VERSION 5.4 ;
NAMESCASESENSITIVE ON ;
BUSBITCHARS "[]" ;
DIVIDERCHAR "/" ;
UNITS
  DATABASE MICRONS 2000 ;
END UNITS
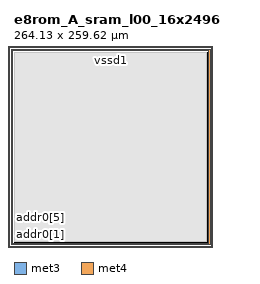
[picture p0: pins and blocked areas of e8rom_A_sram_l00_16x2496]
MACRO e8rom_A_sram_l00_16x2496
   CLASS BLOCK ;
   SIZE 264.13 BY 259.62 ;
   SYMMETRY X Y R90 ;
   PIN clk0
      DIRECTION INPUT ;
      PORT
         LAYER met3 ;
         RECT  -7.48 8.99 -7.1 9.37 ;
      END
   END clk0
   PIN cs0
      DIRECTION INPUT ;
      PORT
         LAYER met4 ;
         RECT  25.365 -7.48 25.745 -7.1 ;
      END
   END cs0
   PIN addr0[0]
      DIRECTION INPUT ;
      PORT
         LAYER met4 ;
         RECT  32.23 -7.48 32.61 -7.1 ;
      END
   END addr0[0]
   PIN addr0[1]
      DIRECTION INPUT ;
      PORT
         LAYER met4 ;
         RECT  34.27 -7.48 34.65 -7.1 ;
      END
   END addr0[1]
   PIN addr0[2]
      DIRECTION INPUT ;
      PORT
         LAYER met4 ;
         RECT  36.31 -7.48 36.69 -7.1 ;
      END
   END addr0[2]
   PIN addr0[3]
      DIRECTION INPUT ;
      PORT
         LAYER met4 ;
         RECT  38.35 -7.48 38.73 -7.1 ;
      END
   END addr0[3]
   PIN addr0[4]
      DIRECTION INPUT ;
      PORT
         LAYER met3 ;
         RECT  -7.48 33.89 -7.1 34.27 ;
      END
   END addr0[4]
   PIN addr0[5]
      DIRECTION INPUT ;
      PORT
         LAYER met3 ;
         RECT  -7.48 33.145 -7.1 33.525 ;
      END
   END addr0[5]
   PIN addr0[6]
      DIRECTION INPUT ;
      PORT
         LAYER met3 ;
         RECT  -7.48 34.635 -7.1 35.015 ;
      END
   END addr0[6]
   PIN addr0[7]
      DIRECTION INPUT ;
      PORT
         LAYER met3 ;
         RECT  -7.48 32.455 -7.1 32.835 ;
      END
   END addr0[7]
   PIN addr0[8]
      DIRECTION INPUT ;
      PORT
         LAYER met3 ;
         RECT  -7.48 35.325 -7.1 35.705 ;
      END
   END addr0[8]
   PIN addr0[9]
      DIRECTION INPUT ;
      PORT
         LAYER met3 ;
         RECT  -7.48 31.765 -7.1 32.145 ;
      END
   END addr0[9]
   PIN addr0[10]
      DIRECTION INPUT ;
      PORT
         LAYER met3 ;
         RECT  -7.48 36.015 -7.1 36.395 ;
      END
   END addr0[10]
   PIN addr0[11]
      DIRECTION INPUT ;
      PORT
         LAYER met3 ;
         RECT  -7.48 31.075 -7.1 31.455 ;
      END
   END addr0[11]
   PIN dout0[0]
      DIRECTION OUTPUT ;
      PORT
         LAYER met4 ;
         RECT  67.235 -7.48 67.615 -7.1 ;
      END
   END dout0[0]
   PIN dout0[1]
      DIRECTION OUTPUT ;
      PORT
         LAYER met4 ;
         RECT  68.775 -7.48 69.155 -7.1 ;
      END
   END dout0[1]
   PIN dout0[2]
      DIRECTION OUTPUT ;
      PORT
         LAYER met4 ;
         RECT  70.315 -7.48 70.695 -7.1 ;
      END
   END dout0[2]
   PIN dout0[3]
      DIRECTION OUTPUT ;
      PORT
         LAYER met4 ;
         RECT  71.855 -7.48 72.235 -7.1 ;
      END
   END dout0[3]
   PIN dout0[4]
      DIRECTION OUTPUT ;
      PORT
         LAYER met4 ;
         RECT  73.395 -7.48 73.775 -7.1 ;
      END
   END dout0[4]
   PIN dout0[5]
      DIRECTION OUTPUT ;
      PORT
         LAYER met4 ;
         RECT  74.935 -7.48 75.315 -7.1 ;
      END
   END dout0[5]
   PIN dout0[6]
      DIRECTION OUTPUT ;
      PORT
         LAYER met4 ;
         RECT  76.475 -7.48 76.855 -7.1 ;
      END
   END dout0[6]
   PIN dout0[7]
      DIRECTION OUTPUT ;
      PORT
         LAYER met4 ;
         RECT  78.015 -7.48 78.395 -7.1 ;
      END
   END dout0[7]
   PIN dout0[8]
      DIRECTION OUTPUT ;
      PORT
         LAYER met4 ;
         RECT  79.555 -7.48 79.935 -7.1 ;
      END
   END dout0[8]
   PIN dout0[9]
      DIRECTION OUTPUT ;
      PORT
         LAYER met4 ;
         RECT  81.095 -7.48 81.475 -7.1 ;
      END
   END dout0[9]
   PIN dout0[10]
      DIRECTION OUTPUT ;
      PORT
         LAYER met4 ;
         RECT  82.635 -7.48 83.015 -7.1 ;
      END
   END dout0[10]
   PIN dout0[11]
      DIRECTION OUTPUT ;
      PORT
         LAYER met4 ;
         RECT  84.175 -7.48 84.555 -7.1 ;
      END
   END dout0[11]
   PIN dout0[12]
      DIRECTION OUTPUT ;
      PORT
         LAYER met4 ;
         RECT  85.715 -7.48 86.095 -7.1 ;
      END
   END dout0[12]
   PIN dout0[13]
      DIRECTION OUTPUT ;
      PORT
         LAYER met4 ;
         RECT  87.255 -7.48 87.635 -7.1 ;
      END
   END dout0[13]
   PIN dout0[14]
      DIRECTION OUTPUT ;
      PORT
         LAYER met4 ;
         RECT  88.795 -7.48 89.175 -7.1 ;
      END
   END dout0[14]
   PIN dout0[15]
      DIRECTION OUTPUT ;
      PORT
         LAYER met4 ;
         RECT  90.335 -7.48 90.715 -7.1 ;
      END
   END dout0[15]
   PIN vccd1
      DIRECTION INOUT ;
      USE POWER ; 
      SHAPE ABUTMENT ; 
      PORT
         LAYER met3 ;
         RECT  -7.48 -7.48 271.61 -5.74 ;
         LAYER met4 ;
         RECT  -7.48 -7.48 -5.74 267.1 ;
         LAYER met4 ;
         RECT  269.87 -7.48 271.61 267.1 ;
         LAYER met3 ;
         RECT  -7.48 265.36 271.61 267.1 ;
      END
   END vccd1
   PIN vssd1
      DIRECTION INOUT ;
      USE GROUND ; 
      SHAPE ABUTMENT ; 
      PORT
         LAYER met4 ;
         RECT  266.39 -4.0 268.13 263.62 ;
         LAYER met3 ;
         RECT  -4.0 261.88 268.13 263.62 ;
         LAYER met4 ;
         RECT  -4.0 -4.0 -2.26 263.62 ;
         LAYER met3 ;
         RECT  -4.0 -4.0 268.13 -2.26 ;
      END
   END vssd1
   OBS
   LAYER  met1 ;
      RECT  0.62 0.62 263.51 259.0 ;
   LAYER  met2 ;
      RECT  0.62 0.62 263.51 259.0 ;
   LAYER  met3 ;
      RECT  0.62 0.62 263.51 259.0 ;
   LAYER  met4 ;
      RECT  0.62 0.62 263.51 259.0 ;
   END
END    e8rom_A_sram_l00_16x2496
END    LIBRARY
